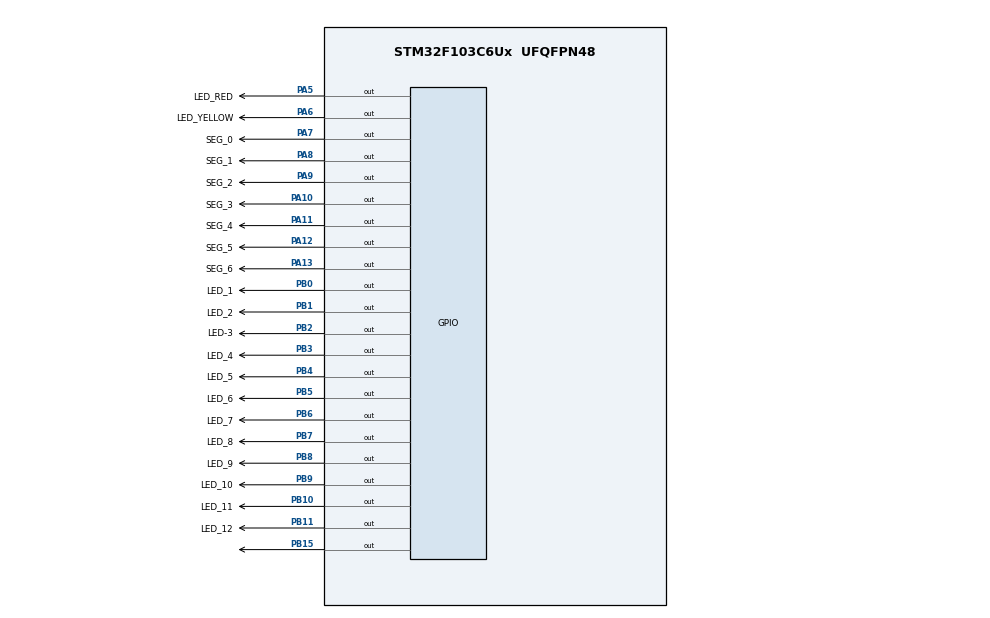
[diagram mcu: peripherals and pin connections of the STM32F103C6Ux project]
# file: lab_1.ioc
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Mcu.Family=STM32F1
Mcu.Name=STM32F103C6Ux
Mcu.Package=UFQFPN48
NVIC.PriorityGroup=NVIC_PRIORITYGROUP_4
PA10.GPIO_Label=SEG_3
PA10.Signal=GPIO_Output
PA11.GPIO_Label=SEG_4
PA11.Signal=GPIO_Output
PA12.GPIO_Label=SEG_5
PA12.Signal=GPIO_Output
PA13.GPIO_Label=SEG_6
PA13.Signal=GPIO_Output
PA5.GPIO_Label=LED_RED
PA5.Signal=GPIO_Output
PA6.GPIO_Label=LED_YELLOW
PA6.Signal=GPIO_Output
PA7.GPIO_Label=SEG_0
PA7.Signal=GPIO_Output
PA8.GPIO_Label=SEG_1
PA8.Signal=GPIO_Output
PA9.GPIO_Label=SEG_2
PA9.Signal=GPIO_Output
PB0.GPIO_Label=LED_1
PB0.Signal=GPIO_Output
PB1.GPIO_Label=LED_2
PB1.Signal=GPIO_Output
PB10.GPIO_Label=LED_11
PB10.Signal=GPIO_Output
PB11.GPIO_Label=LED_12
PB11.Signal=GPIO_Output
PB15.Signal=GPIO_Output
PB2.GPIO_Label=LED-3
PB2.Signal=GPIO_Output
PB3.GPIO_Label=LED_4
PB3.Signal=GPIO_Output
PB4.GPIO_Label=LED_5
PB4.Signal=GPIO_Output
PB5.GPIO_Label=LED_6
PB5.Signal=GPIO_Output
PB6.GPIO_Label=LED_7
PB6.Signal=GPIO_Output
PB7.GPIO_Label=LED_8
PB7.Signal=GPIO_Output
PB8.GPIO_Label=LED_9
PB8.Signal=GPIO_Output
PB9.GPIO_Label=LED_10
PB9.Signal=GPIO_Output
ProjectManager.HeapSize=0x200
ProjectManager.StackSize=0x400
ProjectManager.TargetToolchain=STM32CubeIDE
RCC.APB1Freq_Value=8000000
RCC.APB2Freq_Value=8000000
board=custom

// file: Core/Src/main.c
/* USER CODE BEGIN Header */
/**
  ******************************************************************************
  * @file           : main.c
  * @brief          : Main program body
  ******************************************************************************
  * @attention
  *
  * Copyright (c) 2024 STMicroelectronics.
  * All rights reserved.
  *
  * This software is licensed under terms that can be found in the LICENSE file
  * in the root directory of this software component.
  * If no LICENSE file comes with this software, it is provided AS-IS.
  *
  ******************************************************************************
  */
/* USER CODE END Header */
#include "main.h"

void SystemClock_Config(void);
static void MX_GPIO_Init(void);

/* USER CODE BEGIN 0 */
void display7SEG_Y(int num){
	switch (num) {
	case 0:
		    HAL_GPIO_WritePin(SEG_0_GPIO_Port,SEG_0_Pin,GPIO_PIN_RESET);
		    HAL_GPIO_WritePin(SEG_1_GPIO_Port,SEG_1_Pin,GPIO_PIN_RESET);
		    HAL_GPIO_WritePin(SEG_2_GPIO_Port,SEG_2_Pin,GPIO_PIN_RESET);
		    HAL_GPIO_WritePin(SEG_3_GPIO_Port,SEG_3_Pin,GPIO_PIN_RESET);
		    HAL_GPIO_WritePin(SEG_4_GPIO_Port,SEG_4_Pin,GPIO_PIN_RESET);
		    HAL_GPIO_WritePin(SEG_5_GPIO_Port,SEG_5_Pin,GPIO_PIN_RESET);
		    HAL_GPIO_WritePin(SEG_6_GPIO_Port,SEG_6_Pin,GPIO_PIN_SET);
			break;
	case 1:
		    HAL_GPIO_WritePin(SEG_0_GPIO_Port,SEG_0_Pin,GPIO_PIN_SET);
		    HAL_GPIO_WritePin(SEG_1_GPIO_Port,SEG_1_Pin,GPIO_PIN_RESET);
		    HAL_GPIO_WritePin(SEG_2_GPIO_Port,SEG_2_Pin,GPIO_PIN_RESET);
		    HAL_GPIO_WritePin(SEG_3_GPIO_Port,SEG_3_Pin,GPIO_PIN_SET);
		    HAL_GPIO_WritePin(SEG_4_GPIO_Port,SEG_4_Pin,GPIO_PIN_SET);
		    HAL_GPIO_WritePin(SEG_5_GPIO_Port,SEG_5_Pin,GPIO_PIN_SET);
		    HAL_GPIO_WritePin(SEG_6_GPIO_Port,SEG_6_Pin,GPIO_PIN_SET);
			break;
	case 2:
		    HAL_GPIO_WritePin(SEG_0_GPIO_Port,SEG_0_Pin,GPIO_PIN_RESET);
		    HAL_GPIO_WritePin(SEG_1_GPIO_Port,SEG_1_Pin,GPIO_PIN_RESET);
		    HAL_GPIO_WritePin(SEG_2_GPIO_Port,SEG_2_Pin,GPIO_PIN_SET);
		    HAL_GPIO_WritePin(SEG_3_GPIO_Port,SEG_3_Pin,GPIO_PIN_RESET);
		    HAL_GPIO_WritePin(SEG_4_GPIO_Port,SEG_4_Pin,GPIO_PIN_RESET);
		    HAL_GPIO_WritePin(SEG_5_GPIO_Port,SEG_5_Pin,GPIO_PIN_SET);
		    HAL_GPIO_WritePin(SEG_6_GPIO_Port,SEG_6_Pin,GPIO_PIN_RESET);
			break;
	case 3:
			HAL_GPIO_WritePin(SEG_0_GPIO_Port,SEG_0_Pin,GPIO_PIN_RESET);
			HAL_GPIO_WritePin(SEG_1_GPIO_Port,SEG_1_Pin,GPIO_PIN_RESET);
			HAL_GPIO_WritePin(SEG_2_GPIO_Port,SEG_2_Pin,GPIO_PIN_RESET);
			HAL_GPIO_WritePin(SEG_3_GPIO_Port,SEG_3_Pin,GPIO_PIN_RESET);
			HAL_GPIO_WritePin(SEG_4_GPIO_Port,SEG_4_Pin,GPIO_PIN_SET);
			HAL_GPIO_WritePin(SEG_5_GPIO_Port,SEG_5_Pin,GPIO_PIN_SET);
			HAL_GPIO_WritePin(SEG_6_GPIO_Port,SEG_6_Pin,GPIO_PIN_RESET);
			break;
	case 4:
			HAL_GPIO_WritePin(SEG_0_GPIO_Port,SEG_0_Pin,GPIO_PIN_SET);
			HAL_GPIO_WritePin(SEG_1_GPIO_Port,SEG_1_Pin,GPIO_PIN_RESET);
			HAL_GPIO_WritePin(SEG_2_GPIO_Port,SEG_2_Pin,GPIO_PIN_RESET);
			HAL_GPIO_WritePin(SEG_3_GPIO_Port,SEG_3_Pin,GPIO_PIN_SET);
			HAL_GPIO_WritePin(SEG_4_GPIO_Port,SEG_4_Pin,GPIO_PIN_SET);
			HAL_GPIO_WritePin(SEG_5_GPIO_Port,SEG_5_Pin,GPIO_PIN_RESET);
			HAL_GPIO_WritePin(SEG_6_GPIO_Port,SEG_6_Pin,GPIO_PIN_RESET);
			break;
	case 5:
			HAL_GPIO_WritePin(SEG_0_GPIO_Port,SEG_0_Pin,GPIO_PIN_RESET);
			HAL_GPIO_WritePin(SEG_1_GPIO_Port,SEG_1_Pin,GPIO_PIN_SET);
			HAL_GPIO_WritePin(SEG_2_GPIO_Port,SEG_2_Pin,GPIO_PIN_RESET);
			HAL_GPIO_WritePin(SEG_3_GPIO_Port,SEG_3_Pin,GPIO_PIN_RESET);
			HAL_GPIO_WritePin(SEG_4_GPIO_Port,SEG_4_Pin,GPIO_PIN_SET);
			HAL_GPIO_WritePin(SEG_5_GPIO_Port,SEG_5_Pin,GPIO_PIN_RESET);
			HAL_GPIO_WritePin(SEG_6_GPIO_Port,SEG_6_Pin,GPIO_PIN_RESET);
			break;
	case 6:
			HAL_GPIO_WritePin(SEG_0_GPIO_Port,SEG_0_Pin,GPIO_PIN_RESET);
			HAL_GPIO_WritePin(SEG_1_GPIO_Port,SEG_1_Pin,GPIO_PIN_SET);
			HAL_GPIO_WritePin(SEG_2_GPIO_Port,SEG_2_Pin,GPIO_PIN_RESET);
			HAL_GPIO_WritePin(SEG_3_GPIO_Port,SEG_3_Pin,GPIO_PIN_RESET);
			HAL_GPIO_WritePin(SEG_4_GPIO_Port,SEG_4_Pin,GPIO_PIN_RESET);
			HAL_GPIO_WritePin(SEG_5_GPIO_Port,SEG_5_Pin,GPIO_PIN_RESET);
			HAL_GPIO_WritePin(SEG_6_GPIO_Port,SEG_6_Pin,GPIO_PIN_RESET);
			break;
	case 7:
			HAL_GPIO_WritePin(SEG_0_GPIO_Port,SEG_0_Pin,GPIO_PIN_RESET);
			HAL_GPIO_WritePin(SEG_1_GPIO_Port,SEG_1_Pin,GPIO_PIN_RESET);
			HAL_GPIO_WritePin(SEG_2_GPIO_Port,SEG_2_Pin,GPIO_PIN_RESET);
			HAL_GPIO_WritePin(SEG_3_GPIO_Port,SEG_3_Pin,GPIO_PIN_SET);
			HAL_GPIO_WritePin(SEG_4_GPIO_Port,SEG_4_Pin,GPIO_PIN_SET);
			HAL_GPIO_WritePin(SEG_5_GPIO_Port,SEG_5_Pin,GPIO_PIN_SET);
			HAL_GPIO_WritePin(SEG_6_GPIO_Port,SEG_6_Pin,GPIO_PIN_SET);
			break;
	case 8:
			HAL_GPIO_WritePin(SEG_0_GPIO_Port,SEG_0_Pin,GPIO_PIN_RESET);
			HAL_GPIO_WritePin(SEG_1_GPIO_Port,SEG_1_Pin,GPIO_PIN_RESET);
			HAL_GPIO_WritePin(SEG_2_GPIO_Port,SEG_2_Pin,GPIO_PIN_RESET);
			HAL_GPIO_WritePin(SEG_3_GPIO_Port,SEG_3_Pin,GPIO_PIN_RESET);
			HAL_GPIO_WritePin(SEG_4_GPIO_Port,SEG_4_Pin,GPIO_PIN_RESET);
			HAL_GPIO_WritePin(SEG_5_GPIO_Port,SEG_5_Pin,GPIO_PIN_RESET);
			HAL_GPIO_WritePin(SEG_6_GPIO_Port,SEG_6_Pin,GPIO_PIN_RESET);
			break;
	case 9:
			HAL_GPIO_WritePin(SEG_0_GPIO_Port,SEG_0_Pin,GPIO_PIN_RESET);
			HAL_GPIO_WritePin(SEG_1_GPIO_Port,SEG_1_Pin,GPIO_PIN_RESET);
			HAL_GPIO_WritePin(SEG_2_GPIO_Port,SEG_2_Pin,GPIO_PIN_RESET);
			HAL_GPIO_WritePin(SEG_3_GPIO_Port,SEG_3_Pin,GPIO_PIN_RESET);
			HAL_GPIO_WritePin(SEG_4_GPIO_Port,SEG_4_Pin,GPIO_PIN_SET);
			HAL_GPIO_WritePin(SEG_5_GPIO_Port,SEG_5_Pin,GPIO_PIN_RESET);
			HAL_GPIO_WritePin(SEG_6_GPIO_Port,SEG_6_Pin,GPIO_PIN_RESET);
			break;
	default:
		    HAL_GPIO_WritePin(SEG_0_GPIO_Port,SEG_0_Pin,GPIO_PIN_SET);
			HAL_GPIO_WritePin(SEG_1_GPIO_Port,SEG_1_Pin,GPIO_PIN_SET);
			HAL_GPIO_WritePin(SEG_2_GPIO_Port,SEG_2_Pin,GPIO_PIN_SET);
			HAL_GPIO_WritePin(SEG_3_GPIO_Port,SEG_3_Pin,GPIO_PIN_SET);
			HAL_GPIO_WritePin(SEG_4_GPIO_Port,SEG_4_Pin,GPIO_PIN_SET);
			HAL_GPIO_WritePin(SEG_5_GPIO_Port,SEG_5_Pin,GPIO_PIN_SET);
			HAL_GPIO_WritePin(SEG_6_GPIO_Port,SEG_6_Pin,GPIO_PIN_SET);
			break;
	}
}
void display7SEG_X(int num){
	switch (num) {
	case 0:
		    HAL_GPIO_WritePin(SEG_A_GPIO_Port,SEG_A_Pin,GPIO_PIN_RESET);
		    HAL_GPIO_WritePin(SEG_B_GPIO_Port,SEG_B_Pin,GPIO_PIN_RESET);
		    HAL_GPIO_WritePin(SEG_C_GPIO_Port,SEG_C_Pin,GPIO_PIN_RESET);
		    HAL_GPIO_WritePin(SEG_D_GPIO_Port,SEG_D_Pin,GPIO_PIN_RESET);
		    HAL_GPIO_WritePin(SEG_E_GPIO_Port,SEG_E_Pin,GPIO_PIN_RESET);
		    HAL_GPIO_WritePin(SEG_F_GPIO_Port,SEG_F_Pin,GPIO_PIN_RESET);
		    HAL_GPIO_WritePin(SEG_G_GPIO_Port,SEG_G_Pin,GPIO_PIN_SET);
			break;
	case 1:
		    HAL_GPIO_WritePin(SEG_A_GPIO_Port,SEG_A_Pin,GPIO_PIN_SET);
		    HAL_GPIO_WritePin(SEG_B_GPIO_Port,SEG_B_Pin,GPIO_PIN_RESET);
		    HAL_GPIO_WritePin(SEG_C_GPIO_Port,SEG_C_Pin,GPIO_PIN_RESET);
		    HAL_GPIO_WritePin(SEG_D_GPIO_Port,SEG_D_Pin,GPIO_PIN_SET);
		    HAL_GPIO_WritePin(SEG_E_GPIO_Port,SEG_E_Pin,GPIO_PIN_SET);
		    HAL_GPIO_WritePin(SEG_F_GPIO_Port,SEG_F_Pin,GPIO_PIN_SET);
		    HAL_GPIO_WritePin(SEG_G_GPIO_Port,SEG_G_Pin,GPIO_PIN_SET);
			break;
	case 2:
		    HAL_GPIO_WritePin(SEG_A_GPIO_Port,SEG_A_Pin,GPIO_PIN_RESET);
		    HAL_GPIO_WritePin(SEG_B_GPIO_Port,SEG_B_Pin,GPIO_PIN_RESET);
		    HAL_GPIO_WritePin(SEG_C_GPIO_Port,SEG_C_Pin,GPIO_PIN_SET);
		    HAL_GPIO_WritePin(SEG_D_GPIO_Port,SEG_D_Pin,GPIO_PIN_RESET);
		    HAL_GPIO_WritePin(SEG_E_GPIO_Port,SEG_E_Pin,GPIO_PIN_RESET);
		    HAL_GPIO_WritePin(SEG_F_GPIO_Port,SEG_F_Pin,GPIO_PIN_SET);
		    HAL_GPIO_WritePin(SEG_G_GPIO_Port,SEG_G_Pin,GPIO_PIN_RESET);
			break;
	case 3:
			HAL_GPIO_WritePin(SEG_A_GPIO_Port,SEG_A_Pin,GPIO_PIN_RESET);
			HAL_GPIO_WritePin(SEG_B_GPIO_Port,SEG_B_Pin,GPIO_PIN_RESET);
			HAL_GPIO_WritePin(SEG_C_GPIO_Port,SEG_C_Pin,GPIO_PIN_RESET);
			HAL_GPIO_WritePin(SEG_D_GPIO_Port,SEG_D_Pin,GPIO_PIN_RESET);
			HAL_GPIO_WritePin(SEG_E_GPIO_Port,SEG_E_Pin,GPIO_PIN_SET);
			HAL_GPIO_WritePin(SEG_F_GPIO_Port,SEG_F_Pin,GPIO_PIN_SET);
			HAL_GPIO_WritePin(SEG_G_GPIO_Port,SEG_G_Pin,GPIO_PIN_RESET);
			break;
	case 4:
			HAL_GPIO_WritePin(SEG_A_GPIO_Port,SEG_A_Pin,GPIO_PIN_SET);
			HAL_GPIO_WritePin(SEG_B_GPIO_Port,SEG_B_Pin,GPIO_PIN_RESET);
			HAL_GPIO_WritePin(SEG_C_GPIO_Port,SEG_C_Pin,GPIO_PIN_RESET);
			HAL_GPIO_WritePin(SEG_D_GPIO_Port,SEG_D_Pin,GPIO_PIN_SET);
			HAL_GPIO_WritePin(SEG_E_GPIO_Port,SEG_E_Pin,GPIO_PIN_SET);
			HAL_GPIO_WritePin(SEG_F_GPIO_Port,SEG_F_Pin,GPIO_PIN_RESET);
			HAL_GPIO_WritePin(SEG_G_GPIO_Port,SEG_G_Pin,GPIO_PIN_RESET);
			break;
	case 5:
			HAL_GPIO_WritePin(SEG_A_GPIO_Port,SEG_A_Pin,GPIO_PIN_RESET);
			HAL_GPIO_WritePin(SEG_B_GPIO_Port,SEG_B_Pin,GPIO_PIN_SET);
			HAL_GPIO_WritePin(SEG_C_GPIO_Port,SEG_C_Pin,GPIO_PIN_RESET);
			HAL_GPIO_WritePin(SEG_D_GPIO_Port,SEG_D_Pin,GPIO_PIN_RESET);
			HAL_GPIO_WritePin(SEG_E_GPIO_Port,SEG_E_Pin,GPIO_PIN_SET);
			HAL_GPIO_WritePin(SEG_F_GPIO_Port,SEG_F_Pin,GPIO_PIN_RESET);
			HAL_GPIO_WritePin(SEG_G_GPIO_Port,SEG_G_Pin,GPIO_PIN_RESET);
			break;
	case 6:
			HAL_GPIO_WritePin(SEG_A_GPIO_Port,SEG_A_Pin,GPIO_PIN_RESET);
			HAL_GPIO_WritePin(SEG_B_GPIO_Port,SEG_B_Pin,GPIO_PIN_SET);
			HAL_GPIO_WritePin(SEG_C_GPIO_Port,SEG_C_Pin,GPIO_PIN_RESET);
			HAL_GPIO_WritePin(SEG_D_GPIO_Port,SEG_D_Pin,GPIO_PIN_RESET);
			HAL_GPIO_WritePin(SEG_E_GPIO_Port,SEG_E_Pin,GPIO_PIN_RESET);
			HAL_GPIO_WritePin(SEG_F_GPIO_Port,SEG_F_Pin,GPIO_PIN_RESET);
			HAL_GPIO_WritePin(SEG_G_GPIO_Port,SEG_G_Pin,GPIO_PIN_RESET);
			break;
	case 7:
			HAL_GPIO_WritePin(SEG_A_GPIO_Port,SEG_A_Pin,GPIO_PIN_RESET);
			HAL_GPIO_WritePin(SEG_B_GPIO_Port,SEG_B_Pin,GPIO_PIN_RESET);
			HAL_GPIO_WritePin(SEG_C_GPIO_Port,SEG_C_Pin,GPIO_PIN_RESET);
			HAL_GPIO_WritePin(SEG_D_GPIO_Port,SEG_D_Pin,GPIO_PIN_SET);
			HAL_GPIO_WritePin(SEG_E_GPIO_Port,SEG_E_Pin,GPIO_PIN_SET);
			HAL_GPIO_WritePin(SEG_F_GPIO_Port,SEG_F_Pin,GPIO_PIN_SET);
			HAL_GPIO_WritePin(SEG_G_GPIO_Port,SEG_G_Pin,GPIO_PIN_SET);
			break;
	case 8:
			HAL_GPIO_WritePin(SEG_A_GPIO_Port,SEG_A_Pin,GPIO_PIN_RESET);
			HAL_GPIO_WritePin(SEG_B_GPIO_Port,SEG_B_Pin,GPIO_PIN_RESET);
			HAL_GPIO_WritePin(SEG_C_GPIO_Port,SEG_C_Pin,GPIO_PIN_RESET);
			HAL_GPIO_WritePin(SEG_D_GPIO_Port,SEG_D_Pin,GPIO_PIN_RESET);
			HAL_GPIO_WritePin(SEG_E_GPIO_Port,SEG_E_Pin,GPIO_PIN_RESET);
			HAL_GPIO_WritePin(SEG_F_GPIO_Port,SEG_F_Pin,GPIO_PIN_RESET);
			HAL_GPIO_WritePin(SEG_G_GPIO_Port,SEG_G_Pin,GPIO_PIN_RESET);
			break;
	case 9:
			HAL_GPIO_WritePin(SEG_A_GPIO_Port,SEG_A_Pin,GPIO_PIN_RESET);
			HAL_GPIO_WritePin(SEG_B_GPIO_Port,SEG_B_Pin,GPIO_PIN_RESET);
			HAL_GPIO_WritePin(SEG_C_GPIO_Port,SEG_C_Pin,GPIO_PIN_RESET);
			HAL_GPIO_WritePin(SEG_D_GPIO_Port,SEG_D_Pin,GPIO_PIN_RESET);
			HAL_GPIO_WritePin(SEG_E_GPIO_Port,SEG_E_Pin,GPIO_PIN_SET);
			HAL_GPIO_WritePin(SEG_F_GPIO_Port,SEG_F_Pin,GPIO_PIN_RESET);
			HAL_GPIO_WritePin(SEG_G_GPIO_Port,SEG_G_Pin,GPIO_PIN_RESET);
			break;
	default:
		    HAL_GPIO_WritePin(SEG_A_GPIO_Port,SEG_A_Pin,GPIO_PIN_SET);
			HAL_GPIO_WritePin(SEG_B_GPIO_Port,SEG_B_Pin,GPIO_PIN_SET);
			HAL_GPIO_WritePin(SEG_C_GPIO_Port,SEG_C_Pin,GPIO_PIN_SET);
			HAL_GPIO_WritePin(SEG_D_GPIO_Port,SEG_D_Pin,GPIO_PIN_SET);
			HAL_GPIO_WritePin(SEG_E_GPIO_Port,SEG_E_Pin,GPIO_PIN_SET);
			HAL_GPIO_WritePin(SEG_F_GPIO_Port,SEG_F_Pin,GPIO_PIN_SET);
			HAL_GPIO_WritePin(SEG_G_GPIO_Port,SEG_G_Pin,GPIO_PIN_SET);
			break;
	}
}
/* USER CODE END 0 */

int main(void)
{

  /* MCU Configuration--------------------------------------------------------*/

  /* Reset of all peripherals, Initializes the Flash interface and the Systick. */
  HAL_Init();

  /* Configure the system clock */
  SystemClock_Config();

  /* Initialize all configured peripherals */
  MX_GPIO_Init();

  /* Infinite loop */
  /* USER CODE BEGIN WHILE */
  int counter = 9;
  int LED_Y_CAN_RUN = 1;
  while (1)
  {
     switch (LED_Y_CAN_RUN) {
	  	           case 1:
	  	                if (counter > 2) {
	  	                    HAL_GPIO_WritePin(LED_1_GPIO_Port, LED_1_Pin, GPIO_PIN_RESET);
	  	                    HAL_GPIO_WritePin(LED_2_GPIO_Port, LED_2_Pin, GPIO_PIN_SET);
	  	                    HAL_GPIO_WritePin(LED_3_GPIO_Port, LED_3_Pin, GPIO_PIN_RESET);
	  	                    HAL_GPIO_WritePin(LED_4_GPIO_Port, LED_4_Pin, GPIO_PIN_SET);
	  	                    HAL_GPIO_WritePin(LED_5_GPIO_Port, LED_5_Pin, GPIO_PIN_RESET);
	  	                    HAL_GPIO_WritePin(LED_6_GPIO_Port, LED_6_Pin, GPIO_PIN_RESET);
	  	                    HAL_GPIO_WritePin(LED_7_GPIO_Port, LED_7_Pin, GPIO_PIN_RESET);
	  	                    HAL_GPIO_WritePin(LED_8_GPIO_Port, LED_8_Pin, GPIO_PIN_SET);
	  	                    HAL_GPIO_WritePin(LED_9_GPIO_Port, LED_9_Pin, GPIO_PIN_RESET);
	  	                    HAL_GPIO_WritePin(LED_10_GPIO_Port, LED_10_Pin, GPIO_PIN_SET);
	  	                    HAL_GPIO_WritePin(LED_11_GPIO_Port, LED_11_Pin, GPIO_PIN_RESET);
	  	                    HAL_GPIO_WritePin(LED_12_GPIO_Port, LED_12_Pin, GPIO_PIN_RESET);
	  	                    display7SEG_Y(counter-2);
	  	                    display7SEG_X(counter);
	  	                }
	  	                if (counter <= 2 && counter > 1) {
	  	                    HAL_GPIO_WritePin(LED_1_GPIO_Port, LED_1_Pin, GPIO_PIN_RESET);
	  	                    HAL_GPIO_WritePin(LED_2_GPIO_Port, LED_2_Pin, GPIO_PIN_RESET);
	  	                    HAL_GPIO_WritePin(LED_3_GPIO_Port, LED_3_Pin, GPIO_PIN_SET);
	  	                    HAL_GPIO_WritePin(LED_4_GPIO_Port, LED_4_Pin, GPIO_PIN_SET);
	  	                    HAL_GPIO_WritePin(LED_5_GPIO_Port, LED_5_Pin, GPIO_PIN_RESET);
	  	                    HAL_GPIO_WritePin(LED_6_GPIO_Port, LED_6_Pin, GPIO_PIN_RESET);
	  	                    HAL_GPIO_WritePin(LED_7_GPIO_Port, LED_7_Pin, GPIO_PIN_RESET);
	  	                    HAL_GPIO_WritePin(LED_8_GPIO_Port, LED_8_Pin, GPIO_PIN_RESET);
	  	                    HAL_GPIO_WritePin(LED_9_GPIO_Port, LED_9_Pin, GPIO_PIN_SET);
	  	                    HAL_GPIO_WritePin(LED_10_GPIO_Port, LED_10_Pin, GPIO_PIN_SET);
	  	                    HAL_GPIO_WritePin(LED_11_GPIO_Port, LED_11_Pin, GPIO_PIN_RESET);
	  	                    HAL_GPIO_WritePin(LED_12_GPIO_Port, LED_12_Pin, GPIO_PIN_RESET);
	  	                    display7SEG_Y(counter);
	  	                    display7SEG_X(counter);
	  	                }
	  	                if (counter <= 1) {
	  	                	HAL_GPIO_WritePin(LED_1_GPIO_Port, LED_1_Pin, GPIO_PIN_RESET);
	  	                	HAL_GPIO_WritePin(LED_2_GPIO_Port, LED_2_Pin, GPIO_PIN_RESET);
	  	                    HAL_GPIO_WritePin(LED_3_GPIO_Port, LED_3_Pin, GPIO_PIN_SET);
	  	                	HAL_GPIO_WritePin(LED_4_GPIO_Port, LED_4_Pin, GPIO_PIN_SET);
	  	                    HAL_GPIO_WritePin(LED_5_GPIO_Port, LED_5_Pin, GPIO_PIN_RESET);
	  	                    HAL_GPIO_WritePin(LED_6_GPIO_Port, LED_6_Pin, GPIO_PIN_RESET);
	  	                	HAL_GPIO_WritePin(LED_7_GPIO_Port, LED_7_Pin, GPIO_PIN_RESET);
	  	                	HAL_GPIO_WritePin(LED_8_GPIO_Port, LED_8_Pin, GPIO_PIN_RESET);
	  	                	HAL_GPIO_WritePin(LED_9_GPIO_Port, LED_9_Pin, GPIO_PIN_SET);
	  	                	HAL_GPIO_WritePin(LED_10_GPIO_Port, LED_10_Pin, GPIO_PIN_SET);
	  	                	HAL_GPIO_WritePin(LED_11_GPIO_Port, LED_11_Pin, GPIO_PIN_RESET);
	  	                	HAL_GPIO_WritePin(LED_12_GPIO_Port, LED_12_Pin, GPIO_PIN_RESET);
	  	                	display7SEG_Y(counter);
	  	                	display7SEG_X(counter);
	  	                    counter = 10;
	  	                    LED_Y_CAN_RUN = 0;
	  	                }
	  	                counter--;
	  	                break;

	  	            case 0:
	  	                if (counter > 2) {
	  	                    HAL_GPIO_WritePin(LED_1_GPIO_Port, LED_1_Pin, GPIO_PIN_SET);
	  	                    HAL_GPIO_WritePin(LED_2_GPIO_Port, LED_2_Pin, GPIO_PIN_RESET);
	  	                    HAL_GPIO_WritePin(LED_3_GPIO_Port, LED_3_Pin, GPIO_PIN_RESET);
	  	                    HAL_GPIO_WritePin(LED_4_GPIO_Port, LED_4_Pin, GPIO_PIN_RESET);
	  	                    HAL_GPIO_WritePin(LED_5_GPIO_Port, LED_5_Pin, GPIO_PIN_SET);
	  	                    HAL_GPIO_WritePin(LED_6_GPIO_Port, LED_6_Pin, GPIO_PIN_RESET);
	  	                    HAL_GPIO_WritePin(LED_7_GPIO_Port, LED_7_Pin, GPIO_PIN_SET);
	  	                    HAL_GPIO_WritePin(LED_8_GPIO_Port, LED_8_Pin, GPIO_PIN_RESET);
	  	                    HAL_GPIO_WritePin(LED_9_GPIO_Port, LED_9_Pin, GPIO_PIN_RESET);
	  	                    HAL_GPIO_WritePin(LED_10_GPIO_Port, LED_10_Pin, GPIO_PIN_RESET);
	  	                    HAL_GPIO_WritePin(LED_11_GPIO_Port, LED_11_Pin, GPIO_PIN_SET);
	  	                    HAL_GPIO_WritePin(LED_12_GPIO_Port, LED_12_Pin, GPIO_PIN_RESET);
	  	                    display7SEG_Y(counter);
	  	                   	display7SEG_X(counter-2);
	  	                }
	  	                if (counter <= 2 && counter > 1) {
	  	                    HAL_GPIO_WritePin(LED_1_GPIO_Port, LED_1_Pin, GPIO_PIN_SET);
	  	                    HAL_GPIO_WritePin(LED_2_GPIO_Port, LED_2_Pin, GPIO_PIN_RESET);
	  	                    HAL_GPIO_WritePin(LED_3_GPIO_Port, LED_3_Pin, GPIO_PIN_RESET);
	  	                    HAL_GPIO_WritePin(LED_4_GPIO_Port, LED_4_Pin, GPIO_PIN_RESET);
	  	                    HAL_GPIO_WritePin(LED_5_GPIO_Port, LED_5_Pin, GPIO_PIN_RESET);
	  	                    HAL_GPIO_WritePin(LED_6_GPIO_Port, LED_6_Pin, GPIO_PIN_SET);
	  	                    HAL_GPIO_WritePin(LED_7_GPIO_Port, LED_7_Pin, GPIO_PIN_SET);
	  	                    HAL_GPIO_WritePin(LED_8_GPIO_Port, LED_8_Pin, GPIO_PIN_RESET);
	  	                    HAL_GPIO_WritePin(LED_9_GPIO_Port, LED_9_Pin, GPIO_PIN_RESET);
	  	                    HAL_GPIO_WritePin(LED_10_GPIO_Port, LED_10_Pin, GPIO_PIN_RESET);
	  	                    HAL_GPIO_WritePin(LED_11_GPIO_Port, LED_11_Pin, GPIO_PIN_RESET);
	  	                    HAL_GPIO_WritePin(LED_12_GPIO_Port, LED_12_Pin, GPIO_PIN_SET);
	  	                    display7SEG_Y(counter);
	  	                   	display7SEG_X(counter);
	  	                }
	  	                if (counter <= 1) {
	  	                	HAL_GPIO_WritePin(LED_1_GPIO_Port, LED_1_Pin, GPIO_PIN_SET);
	  	                	HAL_GPIO_WritePin(LED_2_GPIO_Port, LED_2_Pin, GPIO_PIN_RESET);
	  	                	HAL_GPIO_WritePin(LED_3_GPIO_Port, LED_3_Pin, GPIO_PIN_RESET);
	  	                	HAL_GPIO_WritePin(LED_4_GPIO_Port, LED_4_Pin, GPIO_PIN_RESET);
	  	                	HAL_GPIO_WritePin(LED_5_GPIO_Port, LED_5_Pin, GPIO_PIN_RESET);
	  	                	HAL_GPIO_WritePin(LED_6_GPIO_Port, LED_6_Pin, GPIO_PIN_SET);
	  	                	HAL_GPIO_WritePin(LED_7_GPIO_Port, LED_7_Pin, GPIO_PIN_SET);
	  	                	HAL_GPIO_WritePin(LED_8_GPIO_Port, LED_8_Pin, GPIO_PIN_RESET);
	  	                	HAL_GPIO_WritePin(LED_9_GPIO_Port, LED_9_Pin, GPIO_PIN_RESET);
	  	                	HAL_GPIO_WritePin(LED_10_GPIO_Port, LED_10_Pin, GPIO_PIN_RESET);
	  	                	HAL_GPIO_WritePin(LED_11_GPIO_Port, LED_11_Pin, GPIO_PIN_RESET);
	  	                	HAL_GPIO_WritePin(LED_12_GPIO_Port, LED_12_Pin, GPIO_PIN_SET);
	  	                	display7SEG_Y(counter);
	  	                    display7SEG_X(counter);
	  	                    counter = 10;
	  	                    LED_Y_CAN_RUN = 1;
	  	                }
	  	                counter--;
	  	                break;
	  	        }
     HAL_Delay(1000);

    /* USER CODE END WHILE */

  }
}

void SystemClock_Config(void)
{
  RCC_OscInitTypeDef RCC_OscInitStruct = {0};
  RCC_ClkInitTypeDef RCC_ClkInitStruct = {0};

  /** Initializes the RCC Oscillators according to the specified parameters
  * in the RCC_OscInitTypeDef structure.
  */
  RCC_OscInitStruct.OscillatorType = RCC_OSCILLATORTYPE_HSI;
  RCC_OscInitStruct.HSIState = RCC_HSI_ON;
  RCC_OscInitStruct.HSICalibrationValue = RCC_HSICALIBRATION_DEFAULT;
  RCC_OscInitStruct.PLL.PLLState = RCC_PLL_NONE;
  if (HAL_RCC_OscConfig(&RCC_OscInitStruct) != HAL_OK)
  {
    Error_Handler();
  }

  /** Initializes the CPU, AHB and APB buses clocks
  */
  RCC_ClkInitStruct.ClockType = RCC_CLOCKTYPE_HCLK|RCC_CLOCKTYPE_SYSCLK
                              |RCC_CLOCKTYPE_PCLK1|RCC_CLOCKTYPE_PCLK2;
  RCC_ClkInitStruct.SYSCLKSource = RCC_SYSCLKSOURCE_HSI;
  RCC_ClkInitStruct.AHBCLKDivider = RCC_SYSCLK_DIV1;
  RCC_ClkInitStruct.APB1CLKDivider = RCC_HCLK_DIV1;
  RCC_ClkInitStruct.APB2CLKDivider = RCC_HCLK_DIV1;

  if (HAL_RCC_ClockConfig(&RCC_ClkInitStruct, FLASH_LATENCY_0) != HAL_OK)
  {
    Error_Handler();
  }
}

static void MX_GPIO_Init(void)
{
  GPIO_InitTypeDef GPIO_InitStruct = {0};

  /* GPIO Ports Clock Enable */
  __HAL_RCC_GPIOA_CLK_ENABLE();
  __HAL_RCC_GPIOB_CLK_ENABLE();

  /*Configure GPIO pin Output Level */
  HAL_GPIO_WritePin(GPIOA, SEG_A_Pin|SEG_B_Pin|LED_RED_Pin|LED_YELLOW_Pin
                          |SEG_0_Pin|SEG_1_Pin|SEG_2_Pin|SEG_3_Pin
                          |SEG_4_Pin|SEG_5_Pin|SEG_6_Pin|SEG_C_Pin
                          |SEG_D_Pin, GPIO_PIN_RESET);

  /*Configure GPIO pin Output Level */
  HAL_GPIO_WritePin(GPIOB, LED_1_Pin|LED_2_Pin|LED_3_Pin|LED_11_Pin
                          |LED_12_Pin|SEG_E_Pin|SEG_F_Pin|SEG_G_Pin
                          |LED_4_Pin|LED_5_Pin|LED_6_Pin|LED_7_Pin
                          |LED_8_Pin|LED_9_Pin|LED_10_Pin, GPIO_PIN_RESET);

  /*Configure GPIO pins : SEG_A_Pin SEG_B_Pin LED_RED_Pin LED_YELLOW_Pin
                           SEG_0_Pin SEG_1_Pin SEG_2_Pin SEG_3_Pin
                           SEG_4_Pin SEG_5_Pin SEG_6_Pin SEG_C_Pin
                           SEG_D_Pin */
  GPIO_InitStruct.Pin = SEG_A_Pin|SEG_B_Pin|LED_RED_Pin|LED_YELLOW_Pin
                          |SEG_0_Pin|SEG_1_Pin|SEG_2_Pin|SEG_3_Pin
                          |SEG_4_Pin|SEG_5_Pin|SEG_6_Pin|SEG_C_Pin
                          |SEG_D_Pin;
  GPIO_InitStruct.Mode = GPIO_MODE_OUTPUT_PP;
  GPIO_InitStruct.Pull = GPIO_NOPULL;
  GPIO_InitStruct.Speed = GPIO_SPEED_FREQ_LOW;
  HAL_GPIO_Init(GPIOA, &GPIO_InitStruct);

  /*Configure GPIO pins : LED_1_Pin LED_2_Pin LED_3_Pin LED_11_Pin
                           LED_12_Pin SEG_E_Pin SEG_F_Pin SEG_G_Pin
                           LED_4_Pin LED_5_Pin LED_6_Pin LED_7_Pin
                           LED_8_Pin LED_9_Pin LED_10_Pin */
  GPIO_InitStruct.Pin = LED_1_Pin|LED_2_Pin|LED_3_Pin|LED_11_Pin
                          |LED_12_Pin|SEG_E_Pin|SEG_F_Pin|SEG_G_Pin
                          |LED_4_Pin|LED_5_Pin|LED_6_Pin|LED_7_Pin
                          |LED_8_Pin|LED_9_Pin|LED_10_Pin;
  GPIO_InitStruct.Mode = GPIO_MODE_OUTPUT_PP;
  GPIO_InitStruct.Pull = GPIO_NOPULL;
  GPIO_InitStruct.Speed = GPIO_SPEED_FREQ_LOW;
  HAL_GPIO_Init(GPIOB, &GPIO_InitStruct);

}

void Error_Handler(void)
{
  __disable_irq();
  while (1)
  {
  }
}
